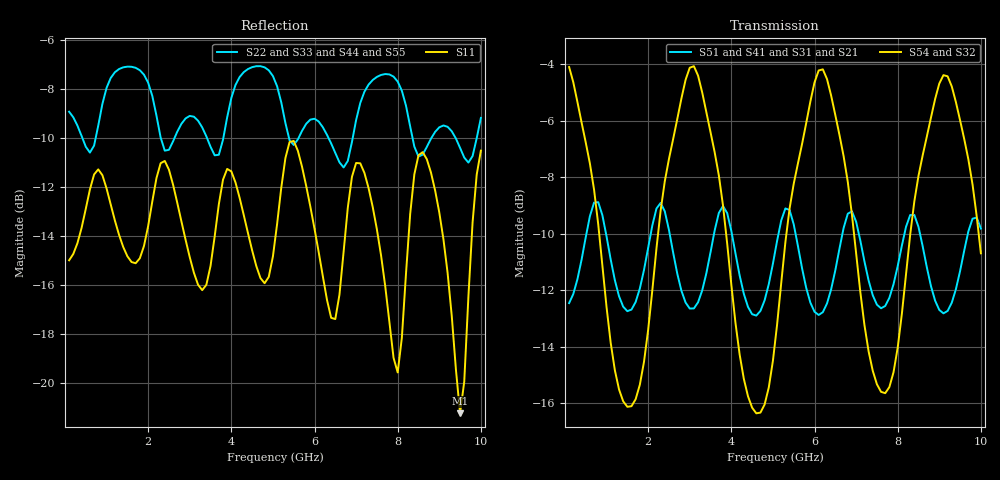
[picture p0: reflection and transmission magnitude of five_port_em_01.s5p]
! freq	mag(S11)	phase(S11)	mag(S12)	phase(S12)	mag(S13)	phase(S13)
!  mag(S14)	phase(S14)	mag(S15)	phase(S15)
!  mag(S21)	phase(S21)	mag(S22)	phase(S22)	mag(S23)	phase(S23)
!  mag(S24)	phase(S24)	mag(S25)	phase(S25)
!  mag(S31)	phase(S31)	mag(S32)	phase(S32)	mag(S33)	phase(S33)
!  mag(S34)	phase(S34)	mag(S35)	phase(S35)
!  mag(S41)	phase(S41)	mag(S42)	phase(S42)	mag(S43)	phase(S43)
!  mag(S44)	phase(S44)	mag(S45)	phase(S45)
!  mag(S51)	phase(S51)	mag(S52)	phase(S52)	mag(S53)	phase(S53)
!  mag(S54)	phase(S54)	mag(S55)	phase(S55)
#  GHz  S  MA  R 50
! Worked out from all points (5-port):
!   100 points, 100 MHz to 10 GHz, reference 50 ohm
!   strongest paths, dB at 100 MHz, 2.6 GHz, 5.1 GHz, 7.6 GHz, 10 GHz:
!     S54: -4.1, -6.7, -13.2, -15.6, -10.7
!     S32: -4.1, -6.7, -13.2, -15.6, -10.7
!     S51: -12.5, -10.7, -10.3, -12.6, -9.8
!     S41: -12.5, -10.7, -10.3, -12.6, -9.8
!     S31: -12.5, -10.7, -10.3, -12.6, -9.8
!     S21: -12.5, -10.7, -10.3, -12.6, -9.8
!   lowest |S11| = -21.2 dB at 9.5 GHz (marker M1), VSWR 1.19, Z = 51.1 + j8.75 ohm
!   |S11| at or under -10 dB: start of sweep to end of sweep
